VERSION 5.7 ;
  NOWIREEXTENSIONATPIN ON ;
  DIVIDERCHAR "/" ;
  BUSBITCHARS "[]" ;
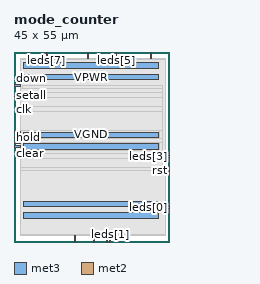
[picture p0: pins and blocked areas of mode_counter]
MACRO mode_counter
  CLASS BLOCK ;
  FOREIGN mode_counter ;
  ORIGIN 0.000 0.000 ;
  SIZE 45.000 BY 55.000 ;
  PIN VGND
    DIRECTION INOUT ;
    USE GROUND ;
    PORT
      LAYER met3 ;
        RECT 2.760 10.220 41.860 11.820 ;
    END
    PORT
      LAYER met3 ;
        RECT 2.760 30.220 41.860 31.820 ;
    END
    PORT
      LAYER met3 ;
        RECT 2.760 50.220 41.860 51.820 ;
    END
  END VGND
  PIN VPWR
    DIRECTION INOUT ;
    USE POWER ;
    PORT
      LAYER met3 ;
        RECT 2.760 6.920 41.860 8.520 ;
    END
    PORT
      LAYER met3 ;
        RECT 2.760 26.920 41.860 28.520 ;
    END
    PORT
      LAYER met3 ;
        RECT 2.760 46.920 41.860 48.520 ;
    END
  END VPWR
  PIN clear
    DIRECTION INPUT ;
    USE SIGNAL ;
    ANTENNAGATEAREA 0.213000 ;
    PORT
      LAYER met3 ;
        RECT 0.000 27.240 2.000 27.840 ;
    END
  END clear
  PIN clk
    DIRECTION INPUT ;
    USE SIGNAL ;
    ANTENNAGATEAREA 0.852000 ;
    PORT
      LAYER met3 ;
        RECT 0.000 38.120 2.000 38.720 ;
    END
  END clk
  PIN down
    DIRECTION INPUT ;
    USE SIGNAL ;
    ANTENNAGATEAREA 0.213000 ;
    PORT
      LAYER met3 ;
        RECT 0.000 44.920 2.000 45.520 ;
    END
  END down
  PIN en
    DIRECTION INPUT ;
    USE SIGNAL ;
    ANTENNAGATEAREA 0.213000 ;
    PORT
      LAYER met3 ;
        RECT 0.000 31.320 2.000 31.920 ;
    END
  END en
  PIN gray
    DIRECTION INPUT ;
    USE SIGNAL ;
    ANTENNAGATEAREA 0.159000 ;
    PORT
      LAYER met2 ;
        RECT 17.570 0.000 17.850 2.000 ;
    END
  END gray
  PIN hold
    DIRECTION INPUT ;
    USE SIGNAL ;
    ANTENNAGATEAREA 0.213000 ;
    PORT
      LAYER met3 ;
        RECT 0.000 29.960 2.000 30.560 ;
    END
  END hold
  PIN leds[0]
    DIRECTION OUTPUT ;
    USE SIGNAL ;
    ANTENNADIFFAREA 0.795200 ;
    PORT
      LAYER met3 ;
        RECT 43.000 9.560 45.000 10.160 ;
    END
  END leds[0]
  PIN leds[1]
    DIRECTION OUTPUT ;
    USE SIGNAL ;
    ANTENNADIFFAREA 0.795200 ;
    PORT
      LAYER met2 ;
        RECT 27.690 0.000 27.970 2.000 ;
    END
  END leds[1]
  PIN leds[2]
    DIRECTION OUTPUT ;
    USE SIGNAL ;
    ANTENNADIFFAREA 0.795200 ;
    PORT
      LAYER met2 ;
        RECT 23.090 0.000 23.370 2.000 ;
    END
  END leds[2]
  PIN leds[3]
    DIRECTION OUTPUT ;
    USE SIGNAL ;
    ANTENNADIFFAREA 0.795200 ;
    PORT
      LAYER met3 ;
        RECT 43.000 24.520 45.000 25.120 ;
    END
  END leds[3]
  PIN leds[4]
    DIRECTION OUTPUT ;
    USE SIGNAL ;
    ANTENNADIFFAREA 0.795200 ;
    PORT
      LAYER met2 ;
        RECT 39.650 53.000 39.930 55.000 ;
    END
  END leds[4]
  PIN leds[5]
    DIRECTION OUTPUT ;
    USE SIGNAL ;
    ANTENNADIFFAREA 0.795200 ;
    PORT
      LAYER met2 ;
        RECT 29.530 53.000 29.810 55.000 ;
    END
  END leds[5]
  PIN leds[6]
    DIRECTION OUTPUT ;
    USE SIGNAL ;
    ANTENNADIFFAREA 0.795200 ;
    PORT
      LAYER met2 ;
        RECT 21.250 53.000 21.530 55.000 ;
    END
  END leds[6]
  PIN leds[7]
    DIRECTION OUTPUT ;
    USE SIGNAL ;
    ANTENNADIFFAREA 0.445500 ;
    PORT
      LAYER met2 ;
        RECT 9.290 53.000 9.570 55.000 ;
    END
  END leds[7]
  PIN rst
    DIRECTION INPUT ;
    USE SIGNAL ;
    ANTENNAGATEAREA 0.159000 ;
    PORT
      LAYER met3 ;
        RECT 43.000 20.440 45.000 21.040 ;
    END
  END rst
  PIN setall
    DIRECTION INPUT ;
    USE SIGNAL ;
    ANTENNAGATEAREA 0.159000 ;
    PORT
      LAYER met3 ;
        RECT 0.000 42.200 2.000 42.800 ;
    END
  END setall
  PIN step3
    DIRECTION INPUT ;
    USE SIGNAL ;
    ANTENNAGATEAREA 0.213000 ;
    PORT
      LAYER met2 ;
        RECT 26.770 0.000 27.050 2.000 ;
    END
  END step3
  PIN tick
    DIRECTION INPUT ;
    USE SIGNAL ;
    ANTENNAGATEAREA 0.213000 ;
    PORT
      LAYER met3 ;
        RECT 0.000 28.600 2.000 29.200 ;
    END
  END tick
  OBS
      LAYER nwell ;
        RECT 2.570 2.635 42.050 51.765 ;
      LAYER li1 ;
        RECT 2.760 2.635 41.860 51.765 ;
      LAYER met1 ;
        RECT 1.910 2.480 43.630 51.920 ;
      LAYER met2 ;
        RECT 1.930 52.720 9.010 53.000 ;
        RECT 9.850 52.720 20.970 53.000 ;
        RECT 21.810 52.720 29.250 53.000 ;
        RECT 30.090 52.720 39.370 53.000 ;
        RECT 40.210 52.720 43.840 53.000 ;
        RECT 1.930 2.280 43.840 52.720 ;
        RECT 1.930 2.000 17.290 2.280 ;
        RECT 18.130 2.000 22.810 2.280 ;
        RECT 23.650 2.000 26.490 2.280 ;
        RECT 27.330 2.000 27.410 2.280 ;
        RECT 28.250 2.000 43.840 2.280 ;
      LAYER met3 ;
        RECT 2.400 44.520 43.000 45.385 ;
        RECT 1.905 43.200 43.000 44.520 ;
        RECT 2.400 41.800 43.000 43.200 ;
        RECT 1.905 39.120 43.000 41.800 ;
        RECT 2.400 37.720 43.000 39.120 ;
        RECT 1.905 32.320 43.000 37.720 ;
        RECT 2.400 32.220 43.000 32.320 ;
        RECT 42.260 29.820 43.000 32.220 ;
        RECT 2.400 28.920 43.000 29.820 ;
        RECT 1.905 26.520 2.360 26.840 ;
        RECT 42.260 26.520 43.000 28.920 ;
        RECT 1.905 25.520 43.000 26.520 ;
        RECT 1.905 24.120 42.600 25.520 ;
        RECT 1.905 21.440 43.000 24.120 ;
        RECT 1.905 20.575 42.600 21.440 ;
  END
END mode_counter
END LIBRARY

